(* Logix 5000 project; controller Electronic_Displays vendor 1 type 14 code 77 rev 17.4; software revision 17.01; part 7 of 7 *)
(* tags used below, declared in another part *)
   Address : STRING;   // "00" = all signs "01" = address 01 "02" = address 02 etc...(see protocol)
   FileLabel : STRING;   // "A" = default etc...(see protocol)
   ENVariable1Update : BOOL;   // 0 = don't update this variable 1 = update this variable
   Variable1Name : STRING;   // Name of variable Default is = U
   Variable1Value : STRING;   // Actual variable1 value, this need to be text format here.
   ENVariable2Update : BOOL;   // 0 = don't update this variable 1 = update this variable
   Variable2Name : STRING;   // Name of variable Default is = V
   Variable2Value : STRING;   // Actual variable2 value, this need to be text format here.
   ENVariable3Update : BOOL;   // 0 = don't update this variable 1 = update this variable
   Variable3Name : STRING;   // Name of variable Default is = W
   Variable3Value : STRING;   // Actual variable3 value, this need to be text format here.
   ENVariable4Update : BOOL;   // 0 = don't update this variable 1 = update this variable
   Variable4Name : STRING;   // Name of variable Default is = X
   Variable4Value : STRING;   // Actual variable4 value, this need to be text format here.
   EN : BOOL;   // Instruction Interface Enable Bit
   DN : BOOL;   // Instruction Interface Done Bit
   ER : BOOL;   // Instruction Interface Error Bit
   map_SignOutput : SINT[496];   // Ethernet/IP LEDSIGN.O Data I/O Mapping
   Packet1Sent : STRING;   // The actual packet sent to the sign (Packet1)
   Packet2Sent : STRING;   // The actual packet sent to the sign (Packet2)
   Packet3Sent : STRING;   // The actual packet sent to the sign (Packet3)
   SEQ : DINT;   // Sequence Number
   InCycle : BOOL;   // Incycle
   Error : BOOL;   // Error
   Done : BOOL;   // Done
   SignETX : STRING;   // DO NOT EDIT = ^C
   SignSOH : STRING;   // DO NOT EDIT = ^A
   SignAddress : STRING;
   SignSTX : STRING;   // DO NOT EDIT = ^B
   SignVariable4Name : STRING;
   SignCommandCode : STRING;   // DO NOT EDIT = B
   SignVariable4Value : STRING;
   SignVariable3Value : STRING;
   TotalPacketCount : DINT[7];   // Total Character Count
   Select : DINT;   // Packet Array Select
   PacketMax : DINT;   // Max Packet Count
   Packet3Offset : DINT;
   Packet2Offset : DINT;
   Packet1Offset : DINT;
   Packet : STRING[7];   // Packet Array to send to sign
(* UpdateSignVariables, continued *)

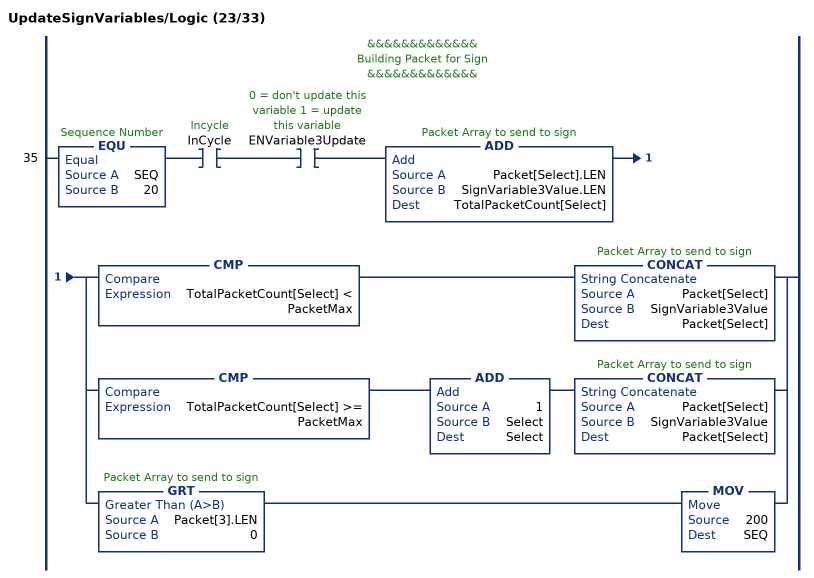
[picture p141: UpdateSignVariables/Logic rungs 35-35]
   // &&&&&&&&&&&&&
   // Building Packet for Sign
   // &&&&&&&&&&&&&
   35: EQU(SEQ,20)XIC(InCycle)XIC(ENVariable3Update)ADD(Packet[Select].LEN,SignVariable3Value.LEN,TotalPacketCount[Select])[CMP(TotalPacketCount[Select] < PacketMax) CONCAT(Packet[Select],SignVariable3Value,Packet[Select]) ,CMP(TotalPacketCount[Select] >= PacketMax) ADD(1,Select,Select) CONCAT(Packet[Select],SignVariable3Value,Packet[Select]) ,GRT(Packet[3].LEN,0) MOV(200,SEQ) ];
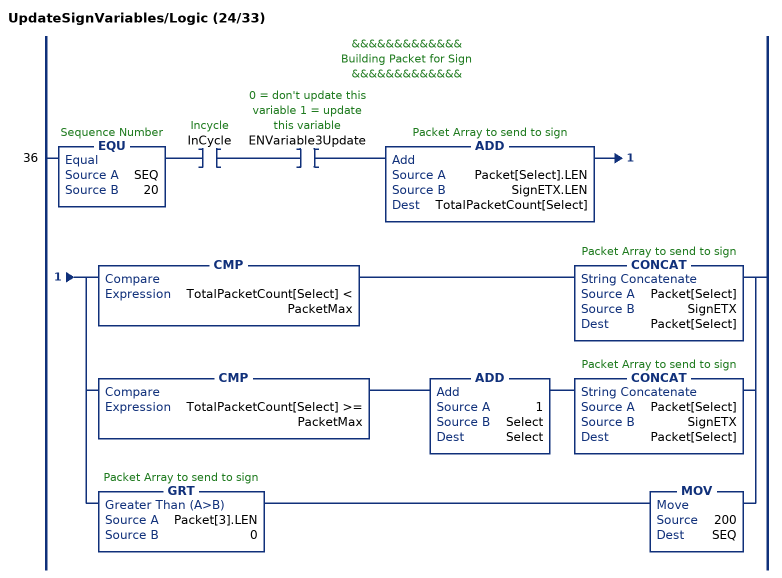
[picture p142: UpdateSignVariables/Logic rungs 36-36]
   // &&&&&&&&&&&&&
   // Building Packet for Sign
   // &&&&&&&&&&&&&
   36: EQU(SEQ,20)XIC(InCycle)XIC(ENVariable3Update)ADD(Packet[Select].LEN,SignETX.LEN,TotalPacketCount[Select])[CMP(TotalPacketCount[Select] < PacketMax) CONCAT(Packet[Select],SignETX,Packet[Select]) ,CMP(TotalPacketCount[Select] >= PacketMax) ADD(1,Select,Select) CONCAT(Packet[Select],SignETX,Packet[Select]) ,GRT(Packet[3].LEN,0) MOV(200,SEQ) ];
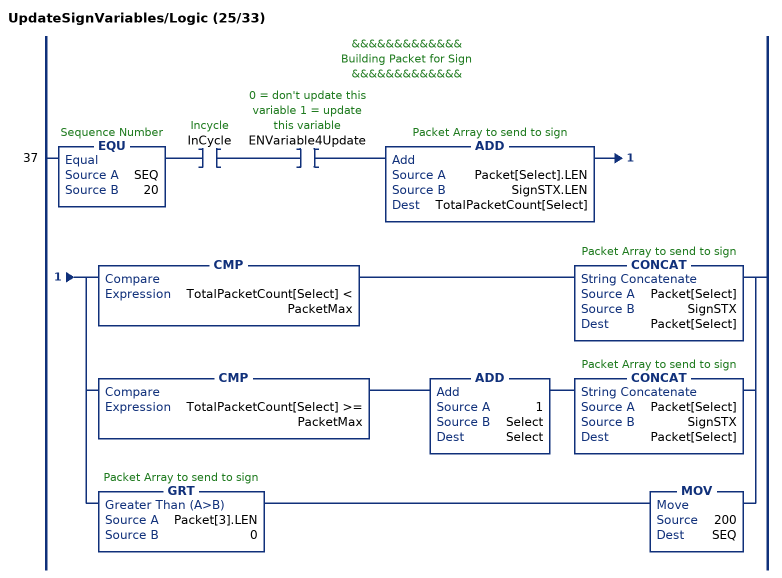
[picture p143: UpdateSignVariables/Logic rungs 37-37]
   // &&&&&&&&&&&&&
   // Building Packet for Sign
   // &&&&&&&&&&&&&
   37: EQU(SEQ,20)XIC(InCycle)XIC(ENVariable4Update)ADD(Packet[Select].LEN,SignSTX.LEN,TotalPacketCount[Select])[CMP(TotalPacketCount[Select] < PacketMax) CONCAT(Packet[Select],SignSTX,Packet[Select]) ,CMP(TotalPacketCount[Select] >= PacketMax) ADD(1,Select,Select) CONCAT(Packet[Select],SignSTX,Packet[Select]) ,GRT(Packet[3].LEN,0) MOV(200,SEQ) ];
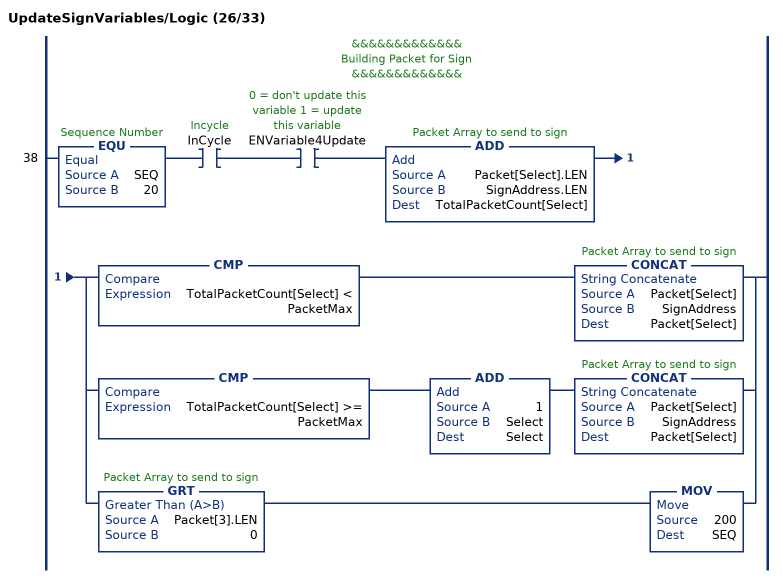
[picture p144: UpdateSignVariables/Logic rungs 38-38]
   // &&&&&&&&&&&&&
   // Building Packet for Sign
   // &&&&&&&&&&&&&
   38: EQU(SEQ,20)XIC(InCycle)XIC(ENVariable4Update)ADD(Packet[Select].LEN,SignAddress.LEN,TotalPacketCount[Select])[CMP(TotalPacketCount[Select] < PacketMax) CONCAT(Packet[Select],SignAddress,Packet[Select]) ,CMP(TotalPacketCount[Select] >= PacketMax) ADD(1,Select,Select) CONCAT(Packet[Select],SignAddress,Packet[Select]) ,GRT(Packet[3].LEN,0) MOV(200,SEQ) ];
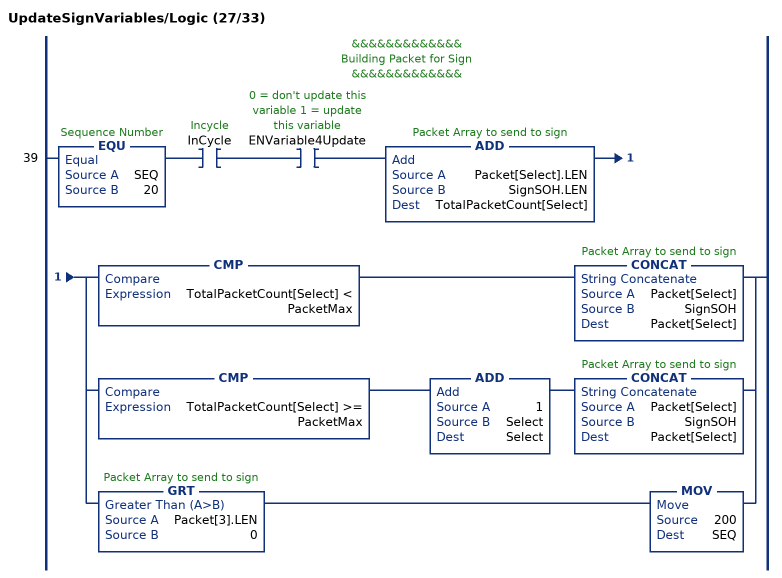
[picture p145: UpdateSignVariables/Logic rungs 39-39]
   // &&&&&&&&&&&&&
   // Building Packet for Sign
   // &&&&&&&&&&&&&
   39: EQU(SEQ,20)XIC(InCycle)XIC(ENVariable4Update)ADD(Packet[Select].LEN,SignSOH.LEN,TotalPacketCount[Select])[CMP(TotalPacketCount[Select] < PacketMax) CONCAT(Packet[Select],SignSOH,Packet[Select]) ,CMP(TotalPacketCount[Select] >= PacketMax) ADD(1,Select,Select) CONCAT(Packet[Select],SignSOH,Packet[Select]) ,GRT(Packet[3].LEN,0) MOV(200,SEQ) ];
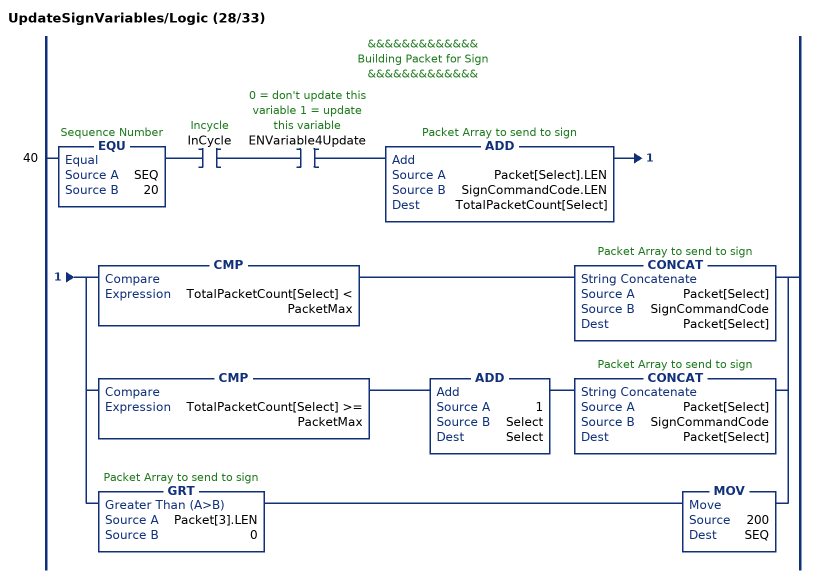
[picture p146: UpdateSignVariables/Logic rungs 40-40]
   // &&&&&&&&&&&&&
   // Building Packet for Sign
   // &&&&&&&&&&&&&
   40: EQU(SEQ,20)XIC(InCycle)XIC(ENVariable4Update)ADD(Packet[Select].LEN,SignCommandCode.LEN,TotalPacketCount[Select])[CMP(TotalPacketCount[Select] < PacketMax) CONCAT(Packet[Select],SignCommandCode,Packet[Select]) ,CMP(TotalPacketCount[Select] >= PacketMax) ADD(1,Select,Select) CONCAT(Packet[Select],SignCommandCode,Packet[Select]) ,GRT(Packet[3].LEN,0) MOV(200,SEQ) ];
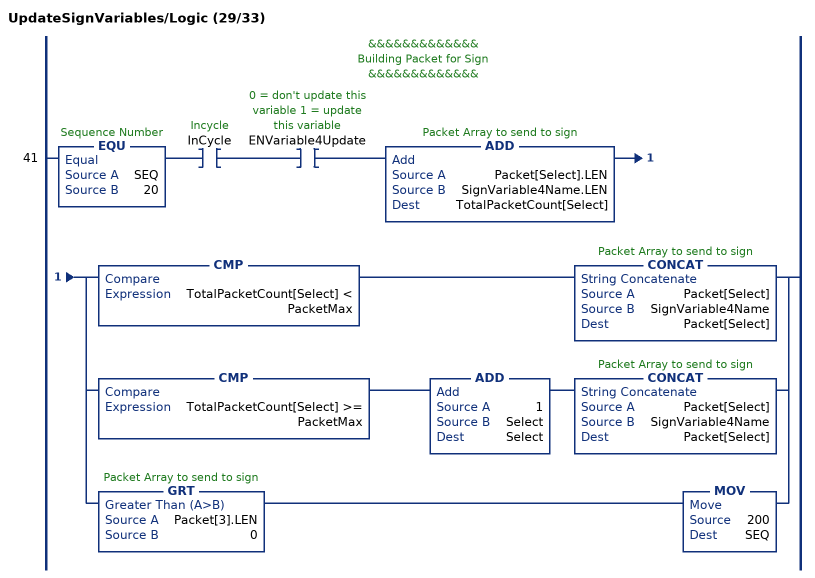
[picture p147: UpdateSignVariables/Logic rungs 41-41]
   // &&&&&&&&&&&&&
   // Building Packet for Sign
   // &&&&&&&&&&&&&
   41: EQU(SEQ,20)XIC(InCycle)XIC(ENVariable4Update)ADD(Packet[Select].LEN,SignVariable4Name.LEN,TotalPacketCount[Select])[CMP(TotalPacketCount[Select] < PacketMax) CONCAT(Packet[Select],SignVariable4Name,Packet[Select]) ,CMP(TotalPacketCount[Select] >= PacketMax) ADD(1,Select,Select) CONCAT(Packet[Select],SignVariable4Name,Packet[Select]) ,GRT(Packet[3].LEN,0) MOV(200,SEQ) ];
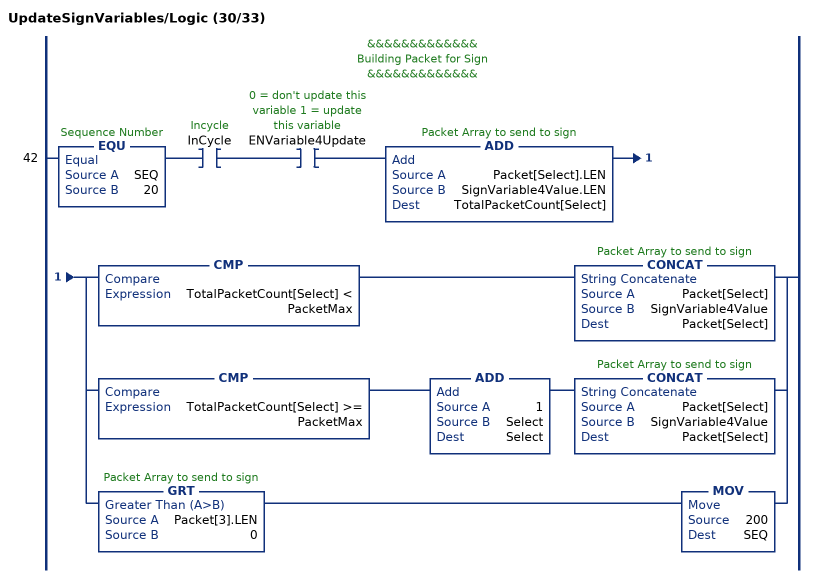
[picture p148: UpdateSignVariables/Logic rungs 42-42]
   // &&&&&&&&&&&&&
   // Building Packet for Sign
   // &&&&&&&&&&&&&
   42: EQU(SEQ,20)XIC(InCycle)XIC(ENVariable4Update)ADD(Packet[Select].LEN,SignVariable4Value.LEN,TotalPacketCount[Select])[CMP(TotalPacketCount[Select] < PacketMax) CONCAT(Packet[Select],SignVariable4Value,Packet[Select]) ,CMP(TotalPacketCount[Select] >= PacketMax) ADD(1,Select,Select) CONCAT(Packet[Select],SignVariable4Value,Packet[Select]) ,GRT(Packet[3].LEN,0) MOV(200,SEQ) ];
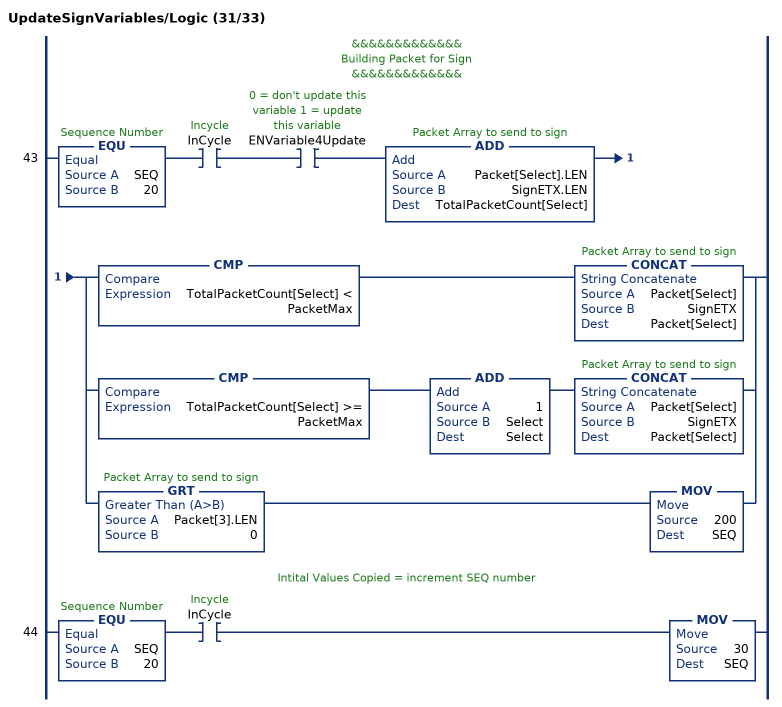
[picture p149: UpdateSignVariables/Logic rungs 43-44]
   // &&&&&&&&&&&&&
   // Building Packet for Sign
   // &&&&&&&&&&&&&
   43: EQU(SEQ,20)XIC(InCycle)XIC(ENVariable4Update)ADD(Packet[Select].LEN,SignETX.LEN,TotalPacketCount[Select])[CMP(TotalPacketCount[Select] < PacketMax) CONCAT(Packet[Select],SignETX,Packet[Select]) ,CMP(TotalPacketCount[Select] >= PacketMax) ADD(1,Select,Select) CONCAT(Packet[Select],SignETX,Packet[Select]) ,GRT(Packet[3].LEN,0) MOV(200,SEQ) ];
   // Intital Values Copied = increment SEQ number
   44: EQU(SEQ,20)XIC(InCycle)MOV(30,SEQ);
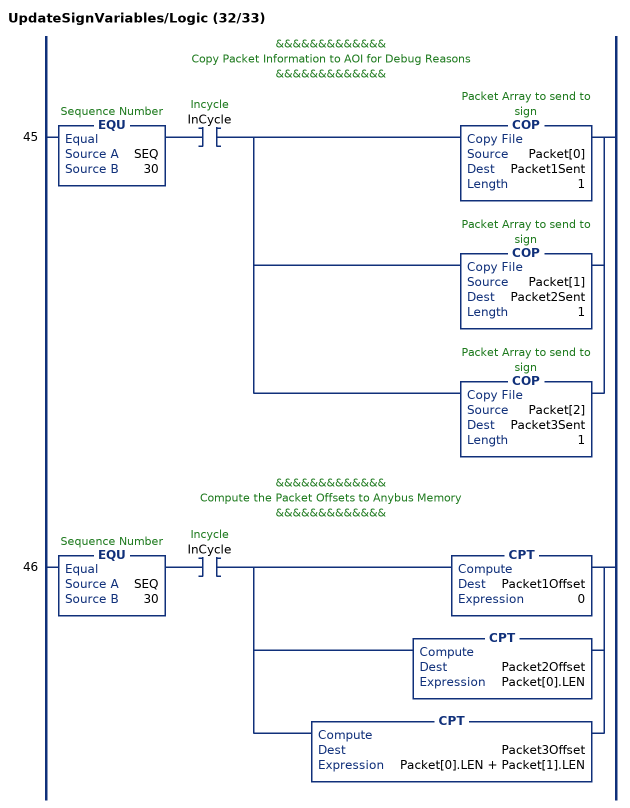
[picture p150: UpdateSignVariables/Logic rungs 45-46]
   // &&&&&&&&&&&&&
   // Copy Packet Information to AOI for Debug Reasons
   // &&&&&&&&&&&&&
   45: EQU(SEQ,30)XIC(InCycle)[COP(Packet[0],Packet1Sent,1) ,COP(Packet[1],Packet2Sent,1) ,COP(Packet[2],Packet3Sent,1) ];
   // &&&&&&&&&&&&&
   // Compute the Packet Offsets to Anybus Memory
   // &&&&&&&&&&&&&
   46: EQU(SEQ,30)XIC(InCycle)[CPT(Packet1Offset,0) ,CPT(Packet2Offset,Packet[0].LEN) ,CPT(Packet3Offset,Packet[0].LEN + Packet[1].LEN) ];
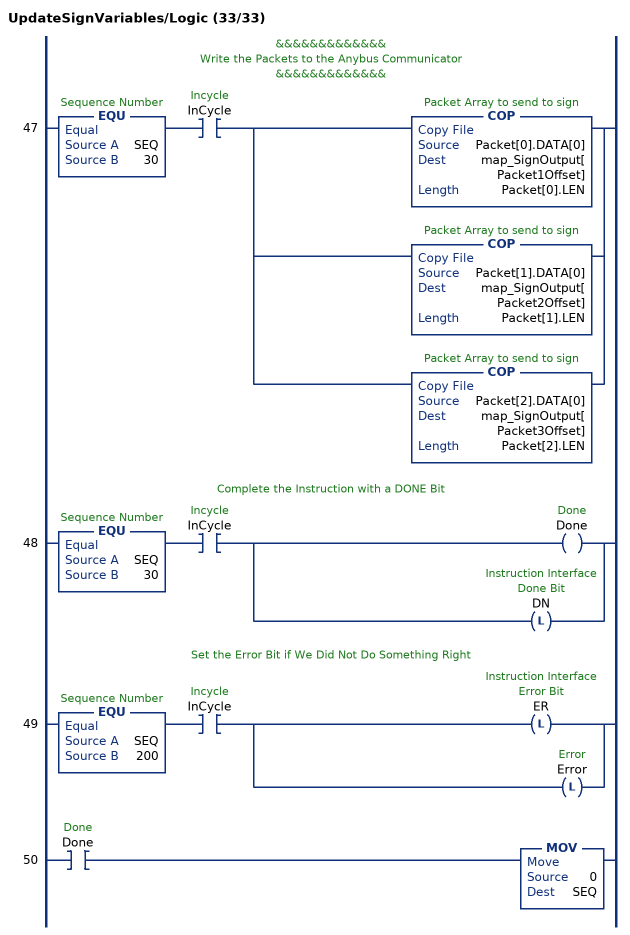
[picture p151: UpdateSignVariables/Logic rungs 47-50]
   // &&&&&&&&&&&&&
   // Write the Packets to the Anybus Communicator
   // &&&&&&&&&&&&&
   47: EQU(SEQ,30)XIC(InCycle)[COP(Packet[0].DATA[0],map_SignOutput[Packet1Offset],Packet[0].LEN) ,COP(Packet[1].DATA[0],map_SignOutput[Packet2Offset],Packet[1].LEN) ,COP(Packet[2].DATA[0],map_SignOutput[Packet3Offset],Packet[2].LEN) ];
   // Complete the Instruction with a DONE Bit
   48: EQU(SEQ,30)XIC(InCycle)[OTE(Done) ,OTL(DN) ];
   // Set the Error Bit if We Did Not Do Something Right
   49: EQU(SEQ,200)XIC(InCycle)[OTL(ER) ,OTL(Error) ];
   50: XIC(Done)MOV(0,SEQ);
END_ROUTINE
END_ADD_ON_INSTRUCTION

VAR_GLOBAL   (* controller tags *)
   ALWAYS_ON : BOOL;
   ColorGreen : STRING := '1';
   ColorRed : STRING := '0';
   Counts_BadParts : DINT := 18;
   Counts_Cycle : STRING := '0.185';
   Counts_GoodParts : DINT := 10118;
   Counts_OEE : STRING := '99.82';
   Counts_TotalParts : DINT := 10136;
   CycleTime : STRING := '0.79299998';
   CycleTimeReal : REAL := 0.173;
   NEVER_ON : BOOL;
   OEE_String : STRING := '99.8224106';
   OEEScore : REAL := 99.82241;
   Sign01 : LEDSIGN := (Address := '01', CommandCode := 'A', FileLabel := 'A', Text1Message := 'Total ', Text2Message := 'Rejects ', Text3Message := 'Cycle Time   ', Text4Message := 'OEE Score    ', TextFont := '0', TextColor := '1', TextAlign := 'L', TextAttribute := '5', TextEffect := 'H', TextSpeed := '3', TextPause := '02', Variable1Name := 'U', Variable2Name := 'V', Variable3Name := 'W', Variable4Name := 'X', Variable1Value := '10136', Variable2Value := '18', Variable3Value := '0.763', Variable4Value := '99.82', VariableFont := '0', VariableColor := '0', VariableAttribute := '4', Packet1Sent := '^B01^ABU10136^C^B01^ABV18^C^B01^ABW0.057^C^B01^ABX99.82^C');
   Sign01Tag0 : ResetSign;
   Sign01Tag1 : SetupSignVariables := (ENVariable1Message := 1, ENVariable2Message := 1, ENVariable3Message := 1, ENVariable4Message := 1);
   Sign01Tag2 : SendSignMessage := (ENText1Message := 1, ENText2Message := 1, ENText3Message := 1, ENText4Message := 1, ENTextFormats := 1, ENVariable1Message := 1, ENVariable2Message := 1, ENVariable3Message := 1, ENVariable4Message := 1, ENVariableFormats := 1);
   Sign01Tag3 : UpdateSignVariables := (ENVariable1Update := 1, ENVariable2Update := 1, ENVariable3Update := 1, ENVariable4Update := 1);
   Sign01Tag4 : ExpertSign;
   Sign02_LD : LEDSIGN := (Address := '02', CommandCode := 'D', FileLabel := 'A', Text1Message := 'Line is Down', TextFont := '3', TextColor := '0', TextAlign := 'F', TextAttribute := '0', TextEffect := 'H', TextSpeed := '2', TextPause := '05', VariableFont := '3', VariableColor := '0', VariableAttribute := '0', Packet1Sent := '^B02^ADA^F3^O0^GFH^H0Line is Down^C');
   Sign02_LineDown : SendSignMessage := (ENText1Message := 1, ENTextFormats := 1);
   Sign02_LineUp : SendSignMessage := (ENText1Message := 1, ENTextFormats := 1, EN := 1, DN := 1);
   Sign02_LU : LEDSIGN := (Address := '02', CommandCode := 'D', FileLabel := 'A', Text1Message := 'Line is Running', TextFont := '2', TextColor := '1', TextAlign := 'F', TextAttribute := '5', TextEffect := 'H', TextSpeed := '3', TextPause := '02', VariableFont := '3', VariableColor := '0', VariableAttribute := '0', Packet1Sent := '^B02^ADA^F2^O1^GFH^H5Line is Running^C');
   Timer02 : TIMER := (PRE := 10000);
   Timer02_1 : TIMER := (PRE := 2000);
   Timer_BadParts : TIMER := (PRE := 10000);
   Timer_GoodParts : TIMER := (PRE := 2000);
   TOGGLE : DINT := 8200;
   Toggle02 : BOOL := 1;
   UpdateSign01Timer : TIMER := (PRE := 1000);
END_VAR

PROGRAM MainProgram   (* main routine MainRoutine *)

ROUTINE MainRoutine   (* ladder *)
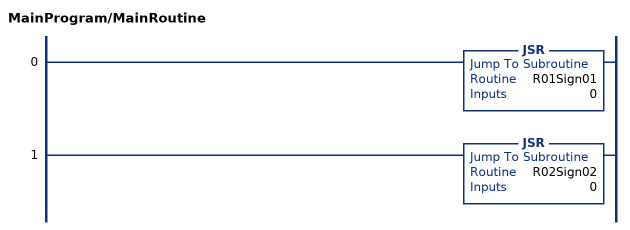
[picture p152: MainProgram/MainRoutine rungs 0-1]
   0: JSR(R01Sign01,0);
   1: JSR(R02Sign02,0);
END_ROUTINE

ROUTINE R01Sign01   (* ladder *)
// Sign Address 01
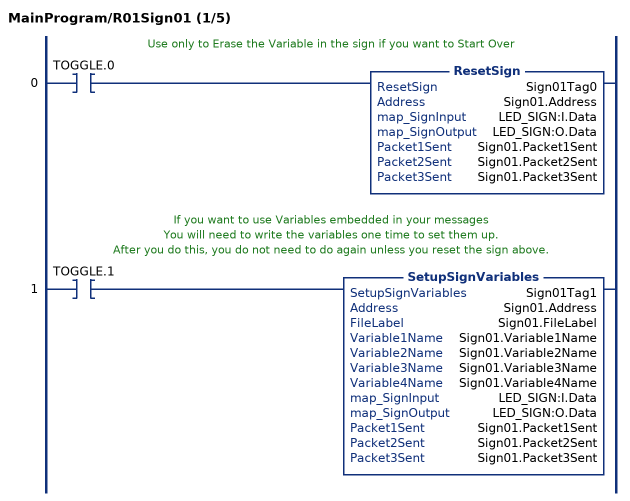
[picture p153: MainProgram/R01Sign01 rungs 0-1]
   // Use only to Erase the Variable in the sign if you want to Start Over
   0: XIC(TOGGLE.0)ResetSign(Sign01Tag0,Sign01.Address,LED_SIGN:I.Data,LED_SIGN:O.Data,Sign01.Packet1Sent,Sign01.Packet2Sent,Sign01.Packet3Sent);
   // If you want to use Variables embedded in your messages
   // You will need to write the variables one time to set them up.
   // After you do this, you do not need to do again unless you reset the sign above.
   1: XIC(TOGGLE.1)SetupSignVariables(Sign01Tag1,Sign01.Address,Sign01.FileLabel,Sign01.Variable1Name,Sign01.Variable2Name,Sign01.Variable3Name,Sign01.Variable4Name,LED_SIGN:I.Data,LED_SIGN:O.Data,Sign01.Packet1Sent,Sign01.Packet2Sent,Sign01.Packet3Sent);
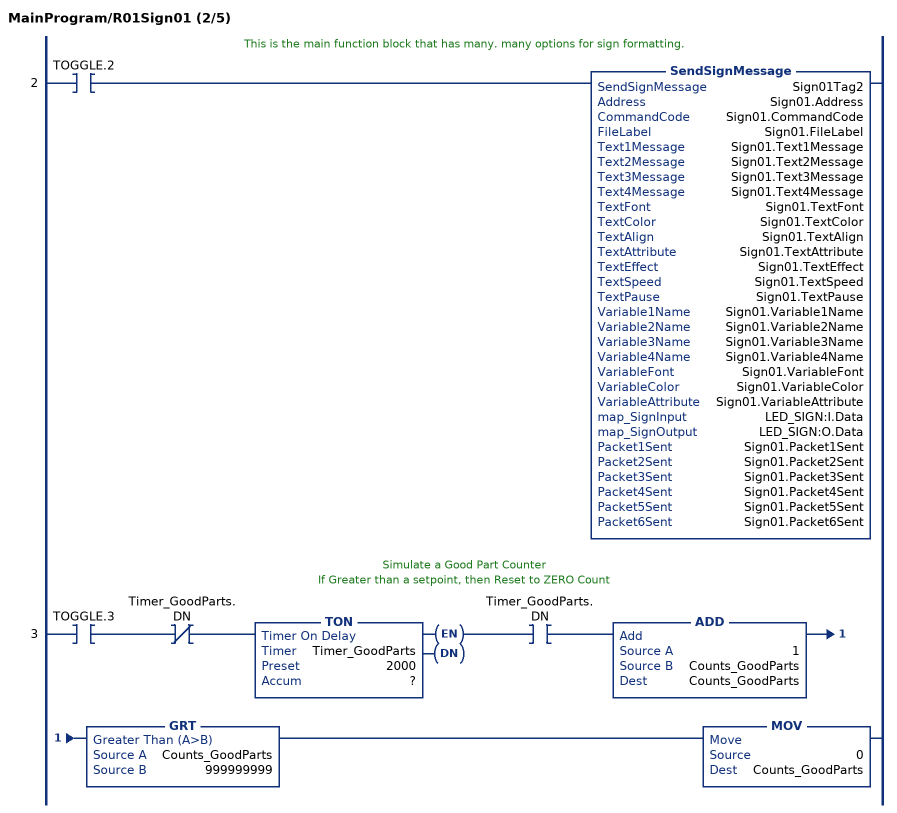
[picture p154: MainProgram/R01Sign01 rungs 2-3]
   // This is the main function block that has many. many options for sign formatting.
   2: XIC(TOGGLE.2)SendSignMessage(Sign01Tag2,Sign01.Address,Sign01.CommandCode,Sign01.FileLabel,Sign01.Text1Message,Sign01.Text2Message,Sign01.Text3Message,Sign01.Text4Message,Sign01.TextFont,Sign01.TextColor,Sign01.TextAlign,Sign01.TextAttribute,Sign01.TextEffect,Sign01.TextSpeed,Sign01.TextPause,Sign01.Variable1Name,Sign01.Variable2Name,Sign01.Variable3Name,Sign01.Variable4Name,Sign01.VariableFont,Sign01.VariableColor,Sign01.VariableAttribute,LED_SIGN:I.Data,LED_SIGN:O.Data,Sign01.Packet1Sent,Sign01.Packet2Sent,Sign01.Packet3Sent,Sign01.Packet4Sent,Sign01.Packet5Sent,Sign01.Packet6Sent);
   // Simulate a Good Part Counter
   // If Greater than a setpoint, then Reset to ZERO Count
   3: XIC(TOGGLE.3)XIO(Timer_GoodParts.DN)TON(Timer_GoodParts,?,?)XIC(Timer_GoodParts.DN)ADD(1,Counts_GoodParts,Counts_GoodParts)GRT(Counts_GoodParts,999999999)MOV(0,Counts_GoodParts);
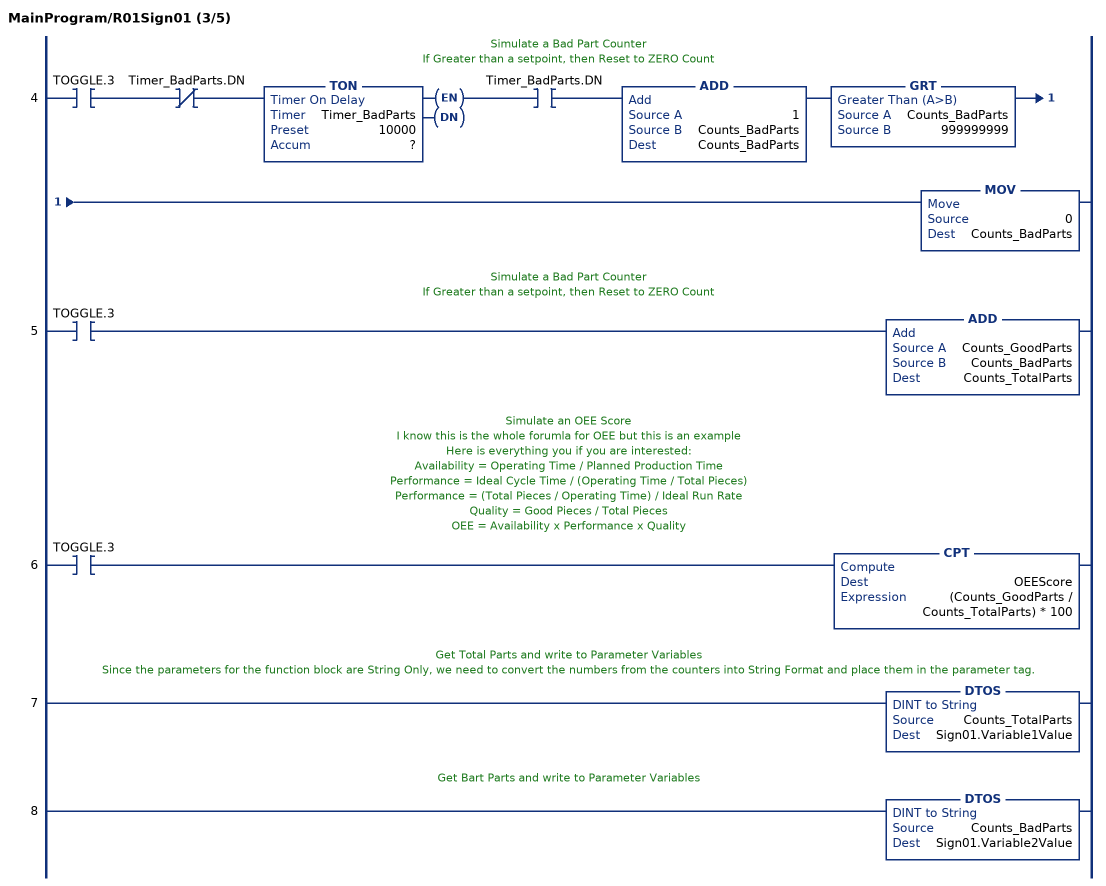
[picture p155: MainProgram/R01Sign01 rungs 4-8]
   // Simulate a Bad Part Counter
   // If Greater than a setpoint, then Reset to ZERO Count
   4: XIC(TOGGLE.3)XIO(Timer_BadParts.DN)TON(Timer_BadParts,?,?)XIC(Timer_BadParts.DN)ADD(1,Counts_BadParts,Counts_BadParts)GRT(Counts_BadParts,999999999)MOV(0,Counts_BadParts);
   // Simulate a Bad Part Counter
   // If Greater than a setpoint, then Reset to ZERO Count
   5: XIC(TOGGLE.3)ADD(Counts_GoodParts,Counts_BadParts,Counts_TotalParts);
   // Simulate an OEE Score
   // I know this is the whole forumla for OEE but this is an example
   // Here is everything you if you are interested:
   // Availability = Operating Time / Planned Production Time
   // Performance = Ideal Cycle Time / (Operating Time / Total Pieces)
   // Performance = (Total Pieces / Operating Time) / Ideal Run Rate
   // Quality = Good Pieces / Total Pieces
   // OEE = Availability x Performance x Quality
   6: XIC(TOGGLE.3)CPT(OEEScore,(Counts_GoodParts / Counts_TotalParts) * 100);
   // Get Total Parts and write to Parameter Variables
   // Since the parameters for the function block are String Only, we need to convert the numbers from the counters into String Format and place them in the parameter tag.
   7: DTOS(Counts_TotalParts,Sign01.Variable1Value);
   // Get Bart Parts and write to Parameter Variables
   8: DTOS(Counts_BadParts,Sign01.Variable2Value);
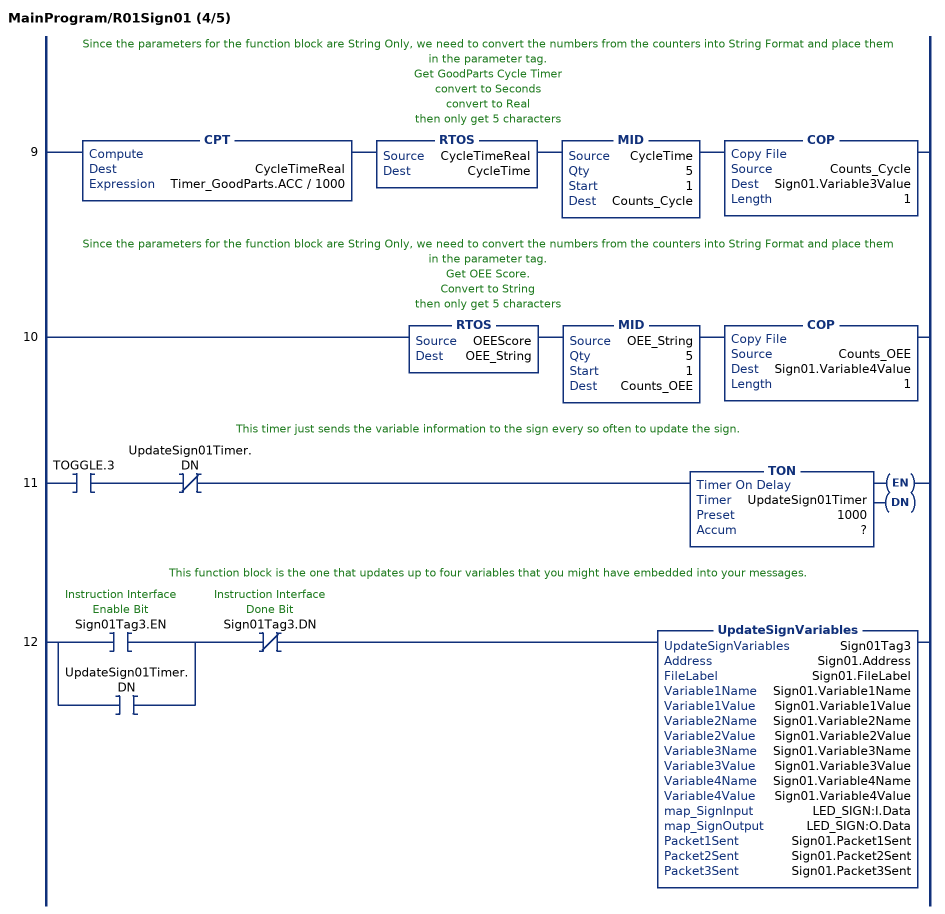
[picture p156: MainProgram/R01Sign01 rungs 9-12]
   // Since the parameters for the function block are String Only, we need to convert the numbers from the counters into String Format and place them in the parameter tag.
   // Get GoodParts Cycle Timer
   // convert to Seconds
   // convert to Real
   // then only get 5 characters
   9: CPT(CycleTimeReal,Timer_GoodParts.ACC / 1000)RTOS(CycleTimeReal,CycleTime)MID(CycleTime,5,1,Counts_Cycle)COP(Counts_Cycle,Sign01.Variable3Value,1);
   // Since the parameters for the function block are String Only, we need to convert the numbers from the counters into String Format and place them in the parameter tag.
   // Get OEE Score.
   // Convert to String
   // then only get 5 characters
   10: RTOS(OEEScore,OEE_String)MID(OEE_String,5,1,Counts_OEE)COP(Counts_OEE,Sign01.Variable4Value,1);
   // This timer just sends the variable information to the sign every so often to update the sign.
   11: XIC(TOGGLE.3)XIO(UpdateSign01Timer.DN)TON(UpdateSign01Timer,?,?);
   // This function block is the one that updates up to four variables that you might have embedded into your messages.
   12: [XIC(Sign01Tag3.EN) ,XIC(UpdateSign01Timer.DN) ]XIO(Sign01Tag3.DN)UpdateSignVariables(Sign01Tag3,Sign01.Address,Sign01.FileLabel,Sign01.Variable1Name,Sign01.Variable1Value,Sign01.Variable2Name,Sign01.Variable2Value,Sign01.Variable3Name,Sign01.Variable3Value,Sign01.Variable4Name,Sign01.Variable4Value,LED_SIGN:I.Data,LED_SIGN:O.Data,Sign01.Packet1Sent,Sign01.Packet2Sent,Sign01.Packet3Sent);
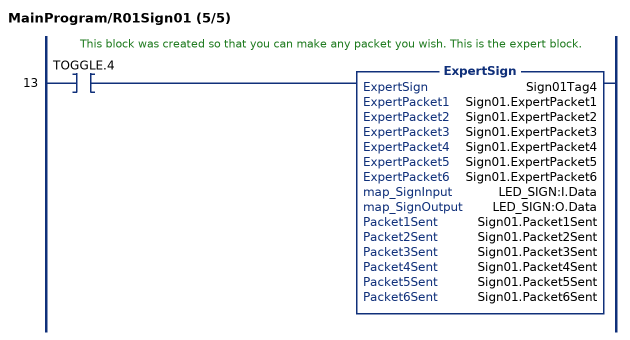
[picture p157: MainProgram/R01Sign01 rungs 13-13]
   // This block was created so that you can make any packet you wish. This is the expert block.
   13: XIC(TOGGLE.4)ExpertSign(Sign01Tag4,Sign01.ExpertPacket1,Sign01.ExpertPacket2,Sign01.ExpertPacket3,Sign01.ExpertPacket4,Sign01.ExpertPacket5,Sign01.ExpertPacket6,LED_SIGN:I.Data,LED_SIGN:O.Data,Sign01.Packet1Sent,Sign01.Packet2Sent,Sign01.Packet3Sent,Sign01.Packet4Sent,Sign01.Packet5Sent,Sign01.Packet6Sent);
END_ROUTINE

ROUTINE R02Sign02   (* ladder *)
// Sign Address 02
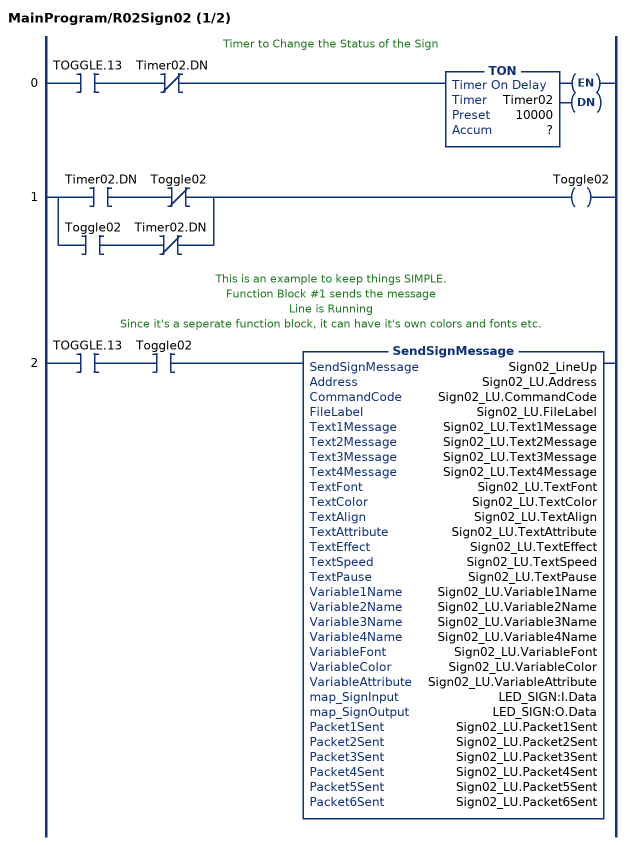
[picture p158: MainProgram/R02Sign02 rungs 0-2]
   // Timer to Change the Status of the Sign
   0: XIC(TOGGLE.13)XIO(Timer02.DN)TON(Timer02,?,?);
   1: [XIC(Timer02.DN) XIO(Toggle02) ,XIC(Toggle02) XIO(Timer02.DN) ]OTE(Toggle02);
   // This is an example to keep things SIMPLE.
   // Function Block #1 sends the message
   // Line is Running
   // Since it's a seperate function block, it can have it's own colors and fonts etc.
   2: XIC(TOGGLE.13)XIC(Toggle02)SendSignMessage(Sign02_LineUp,Sign02_LU.Address,Sign02_LU.CommandCode,Sign02_LU.FileLabel,Sign02_LU.Text1Message,Sign02_LU.Text2Message,Sign02_LU.Text3Message,Sign02_LU.Text4Message,Sign02_LU.TextFont,Sign02_LU.TextColor,Sign02_LU.TextAlign,Sign02_LU.TextAttribute,Sign02_LU.TextEffect,Sign02_LU.TextSpeed,Sign02_LU.TextPause,Sign02_LU.Variable1Name,Sign02_LU.Variable2Name,Sign02_LU.Variable3Name,Sign02_LU.Variable4Name,Sign02_LU.VariableFont,Sign02_LU.VariableColor,Sign02_LU.VariableAttribute,LED_SIGN:I.Data,LED_SIGN:O.Data,Sign02_LU.Packet1Sent,Sign02_LU.Packet2Sent,Sign02_LU.Packet3Sent,Sign02_LU.Packet4Sent,Sign02_LU.Packet5Sent,Sign02_LU.Packet6Sent);
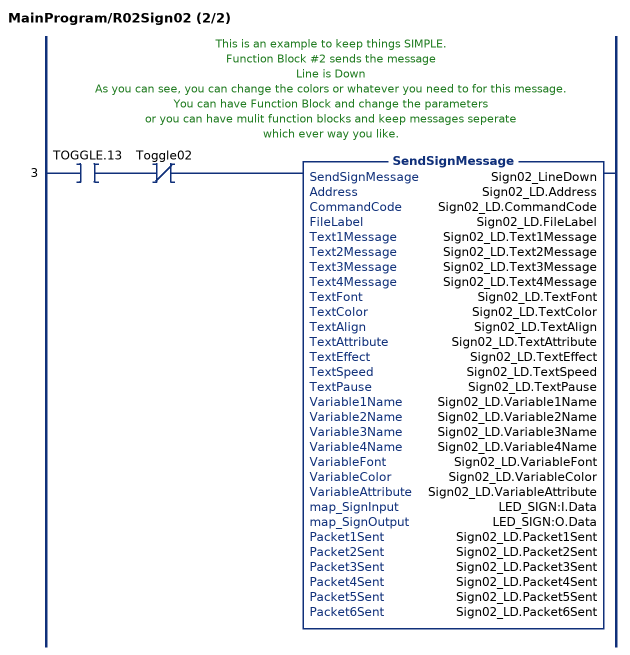
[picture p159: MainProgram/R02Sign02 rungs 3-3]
   // This is an example to keep things SIMPLE.
   // Function Block #2 sends the message
   // Line is Down
   // As you can see, you can change the colors or whatever you need to for this message.
   // You can have Function Block and change the parameters
   // or you can have mulit function blocks and keep messages seperate
   // which ever way you like.
   3: XIC(TOGGLE.13)XIO(Toggle02)SendSignMessage(Sign02_LineDown,Sign02_LD.Address,Sign02_LD.CommandCode,Sign02_LD.FileLabel,Sign02_LD.Text1Message,Sign02_LD.Text2Message,Sign02_LD.Text3Message,Sign02_LD.Text4Message,Sign02_LD.TextFont,Sign02_LD.TextColor,Sign02_LD.TextAlign,Sign02_LD.TextAttribute,Sign02_LD.TextEffect,Sign02_LD.TextSpeed,Sign02_LD.TextPause,Sign02_LD.Variable1Name,Sign02_LD.Variable2Name,Sign02_LD.Variable3Name,Sign02_LD.Variable4Name,Sign02_LD.VariableFont,Sign02_LD.VariableColor,Sign02_LD.VariableAttribute,LED_SIGN:I.Data,LED_SIGN:O.Data,Sign02_LD.Packet1Sent,Sign02_LD.Packet2Sent,Sign02_LD.Packet3Sent,Sign02_LD.Packet4Sent,Sign02_LD.Packet5Sent,Sign02_LD.Packet6Sent);
END_ROUTINE
END_PROGRAM
